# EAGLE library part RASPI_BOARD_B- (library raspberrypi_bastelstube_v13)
Raspberry Pi GPIO connector with markings for the outer dimensions of the Raspberry Pi board model B+ GPIO connector reduced to 26 pins to match models A and B with different sets of drill holes or mounting pads

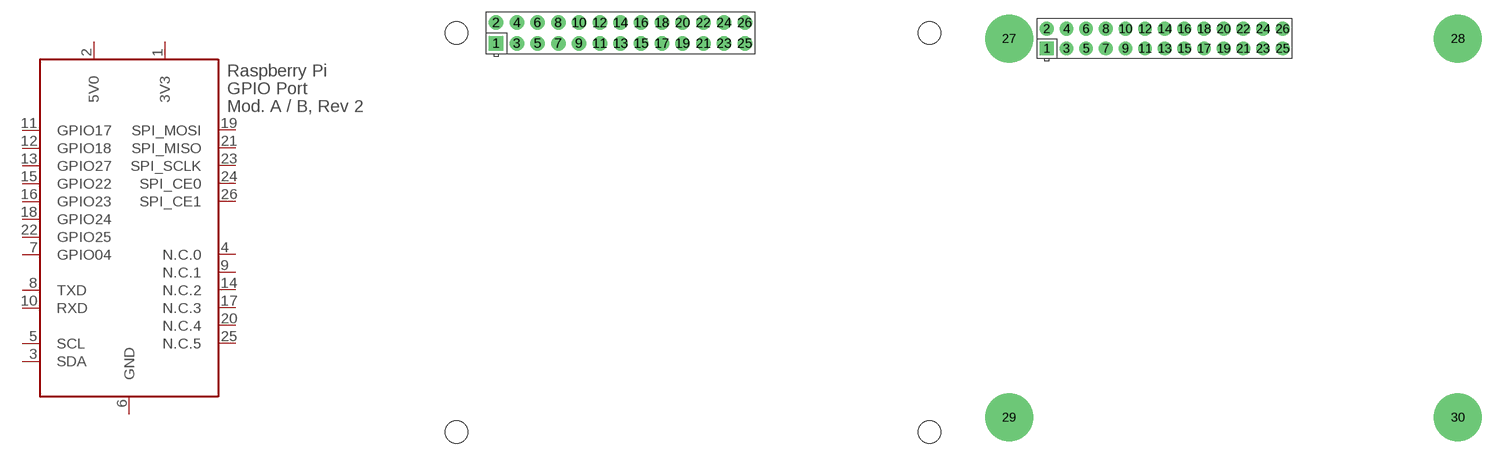
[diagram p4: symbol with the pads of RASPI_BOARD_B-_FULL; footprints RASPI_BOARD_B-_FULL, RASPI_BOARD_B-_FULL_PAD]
Designator prefix X

## RASPI_BOARD_B-_F  [RASPI_BOARD_B-_FULL]
1  3V3  pwr
2  5V0  pwr
3  SDA
4  N.C.0  nc
5  SCL
6  GND  pwr
7  GPIO04
8  TXD
9  N.C.1  nc
10  RXD
11  GPIO17
12  GPIO18
13  GPIO27
14  N.C.2  nc
15  GPIO22
16  GPIO23
17  N.C.3  nc
18  GPIO24
19  SPI_MOSI
20  N.C.4  nc
21  SPI_MISO
22  GPIO25
23  SPI_SCLK
24  SPI_CE0
25  N.C.5  nc
26  SPI_CE1

## RASPI_BOARD_B-_FP  [RASPI_BOARD_B-_FULL_PAD]
Pads as for RASPI_BOARD_B-_FULL

## RASPI_BOARD_B-_E3  [RASPI_BOARD_B-_EDGES_3DRILL]
Pads as for RASPI_BOARD_B-_FULL

## RASPI_BOARD_B-_E3P  [RASPI_BOARD_B-_EDGES_3DRILL_PAD]
Pads as for RASPI_BOARD_B-_FULL

## RASPI_BOARD_B-_E4  [RASPI_BOARD_B-_EDGES_4DRILL]
Pads as for RASPI_BOARD_B-_FULL

## RASPI_BOARD_B-_E4P  [RASPI_BOARD_B-_EDGES_4DRILL_PAD]
Pads as for RASPI_BOARD_B-_FULL

## RASPI_BOARD_B-_E2  [RASPI_BOARD_B-_EDGES_2DRILL]
Pads as for RASPI_BOARD_B-_FULL

## RASPI_BOARD_B-_E2P  [RASPI_BOARD_B-_EDGES_2DRILL_PAD]
Pads as for RASPI_BOARD_B-_FULL

## RASPI_BOARD_B-_E6  [RASPI_BOARD_AB-_EDGES_6DRILL]
Pads as for RASPI_BOARD_B-_FULL

## RASPI_BOARD_B-_E6P  [RASPI_BOARD_AB-_EDGES_6DRILL_PAD]
Pads as for RASPI_BOARD_B-_FULL

## RASPI_BOARD_B-_E5  [RASPI_BOARD_AB-_EDGES_5DRILL]
Pads as for RASPI_BOARD_B-_FULL

## RASPI_BOARD_B-_E5P  [RASPI_BOARD_AB-_EDGES_5DRILL_PAD]
Pads as for RASPI_BOARD_B-_FULL

## RASPI_BOARD_B-_E0  [RASPI_BOARD_B-_EDGES_0DRILL]
Pads as for RASPI_BOARD_B-_FULL

## Footprint RASPI_BOARD_B-_FULL (pad centres in mm)
Raspberry Pi board model B+, full outline with position of big connectors & drill holes GPIO connector reduced to 26 pins to match models A and B
drill 1 pad 1.778 square: 1 8.37,51.23
drill 1 pad 1.778: 2 8.37,53.77; 3 10.91,51.23; 4 10.91,53.77; 5 13.45,51.23; 6 13.45,53.77; 7 15.99,51.23; 8 15.99,53.77; 9 18.53,51.23; 10 18.53,53.77; 11 21.07,51.23; 12 21.07,53.77; 13 23.61,51.23; 14 23.61,53.77; 15 26.15,51.23; 16 26.15,53.77; 17 28.69,51.23; 18 28.69,53.77; 19 31.23,51.23; 20 31.23,53.77; 21 33.77,51.23; 22 33.77,53.77; 23 36.31,51.23; 24 36.31,53.77; 25 38.85,51.23; 26 38.85,53.77
hole 2.75 at 3.5,3.5
hole 2.75 at 3.5,52.5
hole 2.75 at 61.5,3.5
hole 2.75 at 61.5,52.5

## Footprint RASPI_BOARD_B-_FULL_PAD (pad centres in mm)
Raspberry Pi board model B+, full outline with position of big connectors & mounting pads GPIO connector reduced to 26 pins to match models A and B
drill 1 pad 1.778 square: 1 8.37,51.23
drill 1 pad 1.778: 2 8.37,53.77; 3 10.91,51.23; 4 10.91,53.77; 5 13.45,51.23; 6 13.45,53.77; 7 15.99,51.23; 8 15.99,53.77; 9 18.53,51.23; 10 18.53,53.77; 11 21.07,51.23; 12 21.07,53.77; 13 23.61,51.23; 14 23.61,53.77; 15 26.15,51.23; 16 26.15,53.77; 17 28.69,51.23; 18 28.69,53.77; 19 31.23,51.23; 20 31.23,53.77; 21 33.77,51.23; 22 33.77,53.77; 23 36.31,51.23; 24 36.31,53.77; 25 38.85,51.23; 26 38.85,53.77
drill 2.75 pad 6.2: 27 3.5,52.5; 28 61.5,52.5; 29 3.5,3.5; 30 61.5,3.5

## Footprint RASPI_BOARD_B-_EDGES_3DRILL (pad centres in mm)
Raspberry Pi board model B+, outline is only marked by its edges GPIO connector reduced to 26 pins to match models A and B with only 3 drill holes (top left hole is missing to allow routing of power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
drill 1 pad 1.778 square: 1 8.37,51.23
drill 1 pad 1.778: 2 8.37,53.77; 3 10.91,51.23; 4 10.91,53.77; 5 13.45,51.23; 6 13.45,53.77; 7 15.99,51.23; 8 15.99,53.77; 9 18.53,51.23; 10 18.53,53.77; 11 21.07,51.23; 12 21.07,53.77; 13 23.61,51.23; 14 23.61,53.77; 15 26.15,51.23; 16 26.15,53.77; 17 28.69,51.23; 18 28.69,53.77; 19 31.23,51.23; 20 31.23,53.77; 21 33.77,51.23; 22 33.77,53.77; 23 36.31,51.23; 24 36.31,53.77; 25 38.85,51.23; 26 38.85,53.77
hole 2.75 at 3.5,3.5
hole 2.75 at 61.5,3.5
hole 2.75 at 61.5,52.5

## Footprint RASPI_BOARD_B-_EDGES_3DRILL_PAD (pad centres in mm)
Raspberry Pi board model B+, outline is only marked by its edges GPIO connector reduced to 26 pins to match models A and B with only 3 mounting pads (top left hole is missing to allow routing of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
drill 1 pad 1.778 square: 1 8.37,51.23
drill 1 pad 1.778: 2 8.37,53.77; 3 10.91,51.23; 4 10.91,53.77; 5 13.45,51.23; 6 13.45,53.77; 7 15.99,51.23; 8 15.99,53.77; 9 18.53,51.23; 10 18.53,53.77; 11 21.07,51.23; 12 21.07,53.77; 13 23.61,51.23; 14 23.61,53.77; 15 26.15,51.23; 16 26.15,53.77; 17 28.69,51.23; 18 28.69,53.77; 19 31.23,51.23; 20 31.23,53.77; 21 33.77,51.23; 22 33.77,53.77; 23 36.31,51.23; 24 36.31,53.77; 25 38.85,51.23; 26 38.85,53.77
drill 2.75 pad 6.2: 41 3.5,3.5; 42 61.5,3.5; 43 61.5,52.5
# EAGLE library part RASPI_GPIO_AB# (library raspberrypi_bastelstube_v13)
2x13 header connector, all pins connected

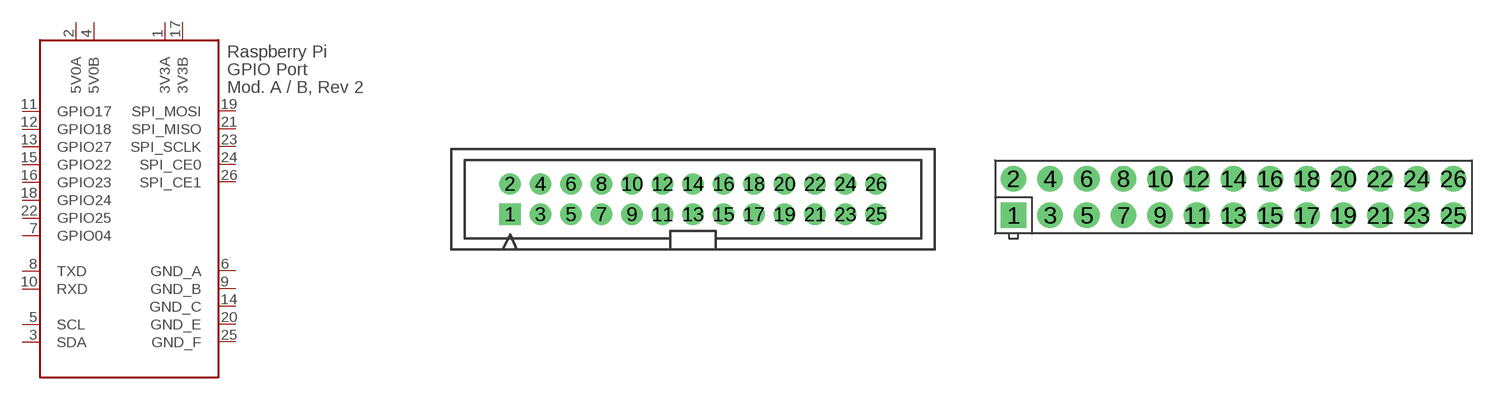
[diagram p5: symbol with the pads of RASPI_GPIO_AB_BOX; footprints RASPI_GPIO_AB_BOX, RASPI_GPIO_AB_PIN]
Designator prefix X

## RASPI_GPIO_AB#_BOX  [RASPI_GPIO_AB_BOX]
1  3V3A  pwr
2  5V0A  pwr
3  SDA
4  5V0B  pwr
5  SCL
6  GND_A  pwr
7  GPIO04
8  TXD
9  GND_B  pwr
10  RXD
11  GPIO17
12  GPIO18
13  GPIO27
14  GND_C  pwr
15  GPIO22
16  GPIO23
17  3V3B  pwr
18  GPIO24
19  SPI_MOSI
20  GND_E  pwr
21  SPI_MISO
22  GPIO25
23  SPI_SCLK
24  SPI_CE0
25  GND_F  pwr
26  SPI_CE1

## RASPI_GPIO_AB#_PIN  [RASPI_GPIO_AB_PIN]
Pads as for RASPI_GPIO_AB_BOX

## Footprint RASPI_GPIO_AB_BOX (pad centres in mm)
26-pin box header for Raspberry Pi GPIO for use with flat ribbon cables
drill 1 pad 1.778 square: 1 -15.24,-1.27
drill 1 pad 1.778: 2 -15.24,1.27; 3 -12.7,-1.27; 4 -12.7,1.27; 5 -10.16,-1.27; 6 -10.16,1.27; 7 -7.62,-1.27; 8 -7.62,1.27; 9 -5.08,-1.27; 10 -5.08,1.27; 11 -2.54,-1.27; 12 -2.54,1.27; 13 0,-1.27; 14 0,1.27; 15 2.54,-1.27; 16 2.54,1.27; 17 5.08,-1.27; 18 5.08,1.27; 19 7.62,-1.27; 20 7.62,1.27; 21 10.16,-1.27; 22 10.16,1.27; 23 12.7,-1.27; 24 12.7,1.27; 25 15.24,-1.27; 26 15.24,1.27

## Footprint RASPI_GPIO_AB_PIN (pad centres in mm)
26-pin connector for Raspberry Pi GPIO just the two rows of pins
drill 1 pad 1.778 square: 1 -15.24,-1.27
drill 1 pad 1.778: 2 -15.24,1.27; 3 -12.7,-1.27; 4 -12.7,1.27; 5 -10.16,-1.27; 6 -10.16,1.27; 7 -7.62,-1.27; 8 -7.62,1.27; 9 -5.08,-1.27; 10 -5.08,1.27; 11 -2.54,-1.27; 12 -2.54,1.27; 13 0,-1.27; 14 0,1.27; 15 2.54,-1.27; 16 2.54,1.27; 17 5.08,-1.27; 18 5.08,1.27; 19 7.62,-1.27; 20 7.62,1.27; 21 10.16,-1.27; 22 10.16,1.27; 23 12.7,-1.27; 24 12.7,1.27; 25 15.24,-1.27; 26 15.24,1.27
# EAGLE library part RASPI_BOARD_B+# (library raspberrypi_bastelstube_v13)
Raspberry Pi GPIO connector with markings for the outer dimensions of the Raspberry Pi board model B+ with different sets of drill holes or mounting pads All pins connected

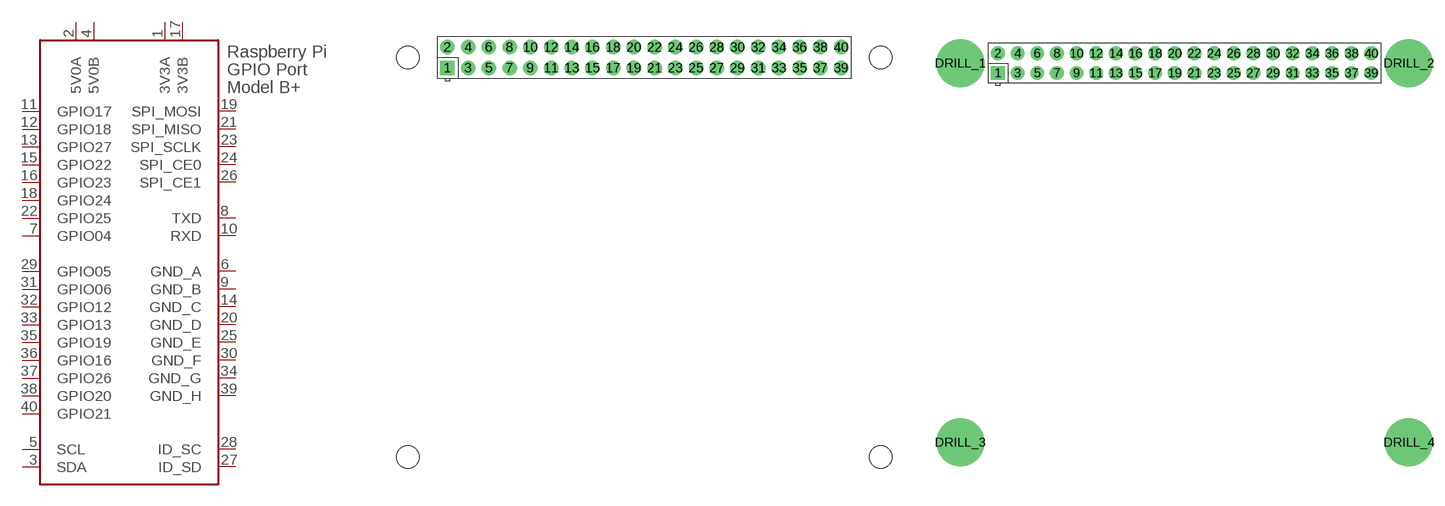
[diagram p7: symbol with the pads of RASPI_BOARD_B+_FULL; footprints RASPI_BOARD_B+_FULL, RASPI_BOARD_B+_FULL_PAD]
Designator prefix X

## RASPI_BOARD_B+#_F  [RASPI_BOARD_B+_FULL]
1  3V3A  pwr
2  5V0A  pwr
3  SDA
4  5V0B  pwr
5  SCL
6  GND_A  pwr
7  GPIO04
8  TXD
9  GND_B  pwr
10  RXD
11  GPIO17
12  GPIO18
13  GPIO27
14  GND_C  pwr
15  GPIO22
16  GPIO23
17  3V3B  pwr
18  GPIO24
19  SPI_MOSI
20  GND_D  pwr
21  SPI_MISO
22  GPIO25
23  SPI_SCLK
24  SPI_CE0
25  GND_E  pwr
26  SPI_CE1
27  ID_SD  nc
28  ID_SC  nc
29  GPIO05  nc
30  GND_F  pwr
31  GPIO06  nc
32  GPIO12  nc
33  GPIO13  nc
34  GND_G  pwr
35  GPIO19  nc
36  GPIO16  nc
37  GPIO26  nc
38  GPIO20  nc
39  GND_H  pwr
40  GPIO21  nc

## RASPI_BOARD_B+#_FP  [RASPI_BOARD_B+_FULL_PAD]
Pads as for RASPI_BOARD_B+_FULL

## RASPI_BOARD_B+#_E0  [RASPI_BOARD_B+_EDGES_0DRILL]
Pads as for RASPI_BOARD_B+_FULL

## RASPI_BOARD_B+#_E3  [RASPI_BOARD_B+_EDGES_3DRILL]
Pads as for RASPI_BOARD_B+_FULL

## RASPI_BOARD_B+#_E3P  [RASPI_BOARD_B+_EDGES_3DRILL_PAD]
Pads as for RASPI_BOARD_B+_FULL

## RASPI_BOARD_B+#_E4  [RASPI_BOARD_B+_EDGES_4DRILL]
Pads as for RASPI_BOARD_B+_FULL

## RASPI_BOARD_B+#_E4P  [RASPI_BOARD_B+_EDGES_4DRILL_PAD]
Pads as for RASPI_BOARD_B+_FULL

## RASPI_BOARD_B+#_H  [RASPI_BOARD_B+HAT]
Pads as for RASPI_BOARD_B+_FULL

## RASPI_BOARD_B+#_HD  [RASPI_BOARD_B+HAT_DF]
Pads as for RASPI_BOARD_B+_FULL

## RASPI_BOARD_B+#_HDC  [RASPI_BOARD_B+HAT_DF_CF]
Pads as for RASPI_BOARD_B+_FULL

## RASPI_BOARD_B+#F  [FE-PI]
Pads as for RASPI_BOARD_B+_FULL

## Footprint RASPI_BOARD_B+_FULL (pad centres in mm)
Raspberry Pi board model B+, full outline with position of big connectors & drill holes
drill 1 pad 1.778 square: 1 8.37,51.23
drill 1 pad 1.778: 2 8.37,53.77; 3 10.91,51.23; 4 10.91,53.77; 5 13.45,51.23; 6 13.45,53.77; 7 15.99,51.23; 8 15.99,53.77; 9 18.53,51.23; 10 18.53,53.77; 11 21.07,51.23; 12 21.07,53.77; 13 23.61,51.23; 14 23.61,53.77; 15 26.15,51.23; 16 26.15,53.77; 17 28.69,51.23; 18 28.69,53.77; 19 31.23,51.23; 20 31.23,53.77; 21 33.77,51.23; 22 33.77,53.77; 23 36.31,51.23; 24 36.31,53.77; 25 38.85,51.23; 26 38.85,53.77; 27 41.39,51.23; 28 41.39,53.77; 29 43.93,51.23; 30 43.93,53.77; 31 46.47,51.23; 32 46.47,53.77; 33 49.01,51.23; 34 49.01,53.77; 35 51.55,51.23; 36 51.55,53.77; 37 54.09,51.23; 38 54.09,53.77; 39 56.63,51.23; 40 56.63,53.77
hole 2.75 at 3.5,3.5
hole 2.75 at 3.5,52.5
hole 2.75 at 61.5,3.5
hole 2.75 at 61.5,52.5

## Footprint RASPI_BOARD_B+_FULL_PAD (pad centres in mm)
Raspberry Pi board model B+, full outline with position of big connectors & mounting pads
drill 1 pad 1.778 square: 1 8.37,51.23
drill 1 pad 1.778: 2 8.37,53.77; 3 10.91,51.23; 4 10.91,53.77; 5 13.45,51.23; 6 13.45,53.77; 7 15.99,51.23; 8 15.99,53.77; 9 18.53,51.23; 10 18.53,53.77; 11 21.07,51.23; 12 21.07,53.77; 13 23.61,51.23; 14 23.61,53.77; 15 26.15,51.23; 16 26.15,53.77; 17 28.69,51.23; 18 28.69,53.77; 19 31.23,51.23; 20 31.23,53.77; 21 33.77,51.23; 22 33.77,53.77; 23 36.31,51.23; 24 36.31,53.77; 25 38.85,51.23; 26 38.85,53.77; 27 41.39,51.23; 28 41.39,53.77; 29 43.93,51.23; 30 43.93,53.77; 31 46.47,51.23; 32 46.47,53.77; 33 49.01,51.23; 34 49.01,53.77; 35 51.55,51.23; 36 51.55,53.77; 37 54.09,51.23; 38 54.09,53.77; 39 56.63,51.23; 40 56.63,53.77
drill 2.75 pad 6.2: DRILL_1 3.5,52.5; DRILL_2 61.5,52.5; DRILL_3 3.5,3.5; DRILL_4 61.5,3.5

## Footprint RASPI_BOARD_B+_EDGES_0DRILL (pad centres in mm)
Raspberry Pi board model B+, outline is only marked by its edges without any drill holes
drill 1 pad 1.778 square: 1 8.37,51.23
drill 1 pad 1.778: 2 8.37,53.77; 3 10.91,51.23; 4 10.91,53.77; 5 13.45,51.23; 6 13.45,53.77; 7 15.99,51.23; 8 15.99,53.77; 9 18.53,51.23; 10 18.53,53.77; 11 21.07,51.23; 12 21.07,53.77; 13 23.61,51.23; 14 23.61,53.77; 15 26.15,51.23; 16 26.15,53.77; 17 28.69,51.23; 18 28.69,53.77; 19 31.23,51.23; 20 31.23,53.77; 21 33.77,51.23; 22 33.77,53.77; 23 36.31,51.23; 24 36.31,53.77; 25 38.85,51.23; 26 38.85,53.77; 27 41.39,51.23; 28 41.39,53.77; 29 43.93,51.23; 30 43.93,53.77; 31 46.47,51.23; 32 46.47,53.77; 33 49.01,51.23; 34 49.01,53.77; 35 51.55,51.23; 36 51.55,53.77; 37 54.09,51.23; 38 54.09,53.77; 39 56.63,51.23; 40 56.63,53.77

## Footprint RASPI_BOARD_B+_EDGES_3DRILL (pad centres in mm)
Raspberry Pi board model B+, outline is only marked by its edges with 3 drill holes (top left hole is missing to allow routing of power supply lines)
drill 1 pad 1.778 square: 1 8.37,51.23
drill 1 pad 1.778: 2 8.37,53.77; 3 10.91,51.23; 4 10.91,53.77; 5 13.45,51.23; 6 13.45,53.77; 7 15.99,51.23; 8 15.99,53.77; 9 18.53,51.23; 10 18.53,53.77; 11 21.07,51.23; 12 21.07,53.77; 13 23.61,51.23; 14 23.61,53.77; 15 26.15,51.23; 16 26.15,53.77; 17 28.69,51.23; 18 28.69,53.77; 19 31.23,51.23; 20 31.23,53.77; 21 33.77,51.23; 22 33.77,53.77; 23 36.31,51.23; 24 36.31,53.77; 25 38.85,51.23; 26 38.85,53.77; 27 41.39,51.23; 28 41.39,53.77; 29 43.93,51.23; 30 43.93,53.77; 31 46.47,51.23; 32 46.47,53.77; 33 49.01,51.23; 34 49.01,53.77; 35 51.55,51.23; 36 51.55,53.77; 37 54.09,51.23; 38 54.09,53.77; 39 56.63,51.23; 40 56.63,53.77
hole 2.75 at 3.5,3.5
hole 2.75 at 61.5,3.5
hole 2.75 at 61.5,52.5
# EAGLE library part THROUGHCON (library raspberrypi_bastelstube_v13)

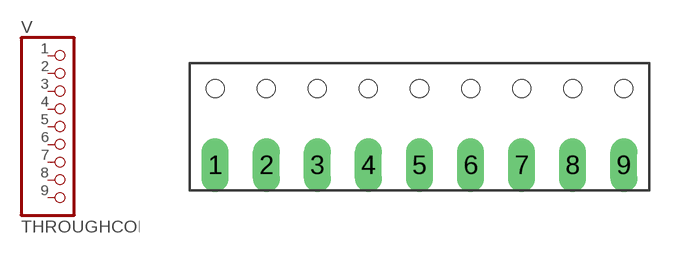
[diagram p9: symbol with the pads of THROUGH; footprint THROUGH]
Designator prefix V

## THROUGHCON  [THROUGH]
1  1  pas
2  2  pas
3  3  pas
4  4  pas
5  5  pas
6  6  pas
7  7  pas
8  8  pas
9  9  pas

## Footprint THROUGH (pad centres in mm)
16-DIP, 2.54 mm (0.10 in) pitch, 7.62 mm (0.30 in) span, 19.69 X 6.60 X 5.08 mm body 16-pin DIP package with 2.54 mm (0.10 in) pitch, 7.62 mm (0.30 in) span with body size 19.69 X 6.60 X 5.08 mm
drill 0.743 pad 1.343 long: 1 -10.16,-3.81; 2 -7.62,-3.81; 3 -5.08,-3.81; 4 -2.54,-3.81; 5 0,-3.81; 6 2.54,-3.81; 7 5.08,-3.81; 8 7.62,-3.81; 9 10.16,-3.81
hole 0.9 at 0,0
hole 0.9 at -2.54,0
hole 0.9 at -5.08,0
hole 0.9 at -7.62,0
hole 0.9 at -10.16,0
hole 0.9 at 2.54,0
hole 0.9 at 5.08,0
hole 0.9 at 7.62,0
hole 0.9 at 10.16,0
